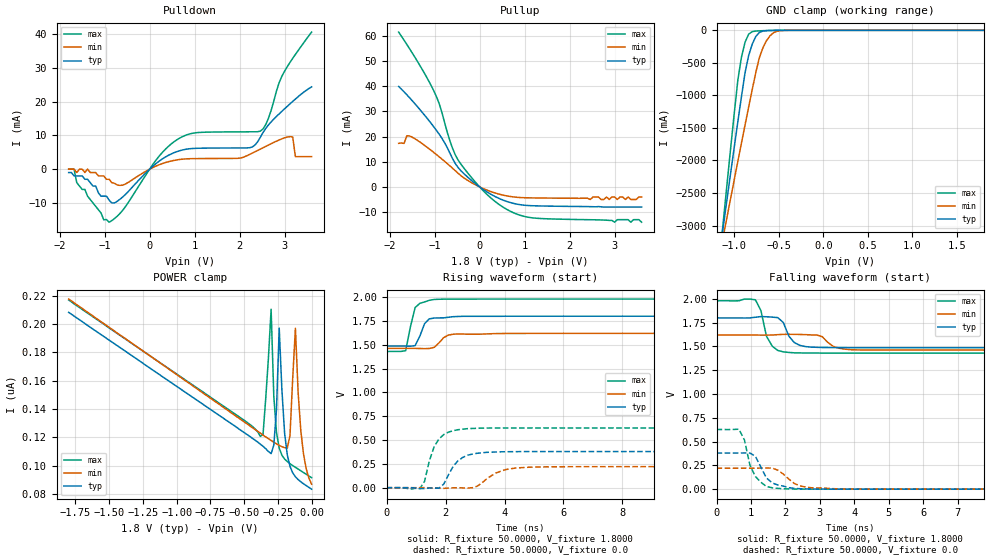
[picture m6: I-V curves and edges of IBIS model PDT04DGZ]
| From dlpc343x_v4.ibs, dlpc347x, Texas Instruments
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[Model]  PDT04DGZ
Model_type 3-state
Polarity   Non-Inverting
Enable   Active-Low
Vmeas =  0.9000V
Cref =   50.0000pF
Rref =   1.0000M
Vref =   0.0V
C_comp   3.2541pF   3.1467pF   3.3974pF
[Temperature Range]   25.0000   0.1250k   -40.0000
[Voltage Range]   1.8000V   1.6200V   1.9800V
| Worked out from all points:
|   slope of the pulldown table from 0 to 0.27 V, typ, clamps not added: 92.6 ohm
|   slope of the pullup table from 0 to 0.27 V, typ, clamps not added: 86.5 ohm
|   GND clamp passes 1 mA (typ) near -0.54 V on its own axis
|   rising waveform, R_fixture 50.0000, V_fixture 1.8000: 20-80 % time 276ps typ, 328ps min, 238ps max; typ from 1.49 V to 1.8 V
|   rising waveform, R_fixture 50.0000, V_fixture 0.0: 20-80 % time 517ps typ, 705ps min, 424ps max; typ from 0 V to 0.379 V
|   falling waveform, R_fixture 50.0000, V_fixture 1.8000: 20-80 % time 282ps typ, 344ps min, 265ps max; typ from 1.8 V to 1.49 V
|   falling waveform, R_fixture 50.0000, V_fixture 0.0: 20-80 % time 398ps typ, 492ps min, 329ps max; typ from 0.379 V to 0 V
[Pulldown]
|Voltage   I(typ)   I(min)   I(max)
-1.8V     -1mA       0A         0A
-1.68V    -2mA       0A         0A
-900mV    -9.2mA     -3mA       -15.7mA
-600mV    -8.247mA   -4.74mA    -12.2mA
180mV     2.06mA     1.128mA    3.334mA
660mV     5.425mA    2.846mA    9.134mA
2.22V     6.337mA    4.345mA    11.06mA
2.52V     10.83mA    6.324mA    11.9mA
2.88V     16.38mA    8.646mA    25.67mA
3.18V     20.05mA    9.514mA    32.79mA
3.24V     20.75mA    3.692mA    33.96mA
3.6V      24.35mA    3.723mA    40.57mA
[Pullup]
|Voltage   I(typ)   I(min)   I(max)
-1.8V     39.86mA    17.29mA    61.43mA
-1.68V    37.72mA    17.27mA    58.22mA
-1.62V    36.59mA    20.27mA    56.57mA
-1.56V    35.43mA    20.24mA    54.9mA
-1.02V    23.85mA    13.67mA    38.14mA
-900mV    20.92mA    11.94mA    33.07mA
-660mV    13.35mA    8.32mA     18.22mA
-480mV    7.708mA    5.429mA    10.67mA
0V        -6.53nA    -5.77nA    -7.26nA
360mV     -3.971mA   -2.5mA     -6.018mA
1.14V     -7.444mA   -4.354mA   -12.2mA
3.6V      -8mA       -4mA       -14mA
[GND_clamp]
|Voltage   I(typ)   I(min)   I(max)
-1.8V     -9.929A    -8.053A    -12.56A
-1.16V    -3.375A    -3.424A    -3.437A
-1.12V    -2.974A    -3.138A    -2.882A
-1.08V    -2.574A    -2.854A    -2.333A
-960mV    -1.399A    -2.009A    -757mA
-920mV    -1.019A    -1.731A    -410.8mA
-880mV    -652.7mA   -1.455A    -184.5mA
-800mV    -215.1mA   -916mA     -20.59mA
-720mV    -33.9mA    -424.5mA   -7.959mA
-680mV    -11.5mA    -271.8mA   -5.67mA
-520mV    -735.3uA   -14.09mA   -620.1uA
1.8V      83.53nA    112.5nA    80.6nA
[POWER_clamp]
|Voltage   I(typ)   I(min)   I(max)
-1.8V     208.3nA    217.7nA    217nA
-380mV    115.3nA    123.1nA    120.8nA
-360mV    113.8nA    121.7nA    122.1nA
-300mV    108.6nA    117.9nA    210.5nA
-280mV    114.6nA    116.7nA    148.9nA
-260mV    139.9nA    115.5nA    123.4nA
-240mV    197.2nA    114.4nA    112.5nA
-200mV    123nA      112.8nA    104.8nA
-160mV    99.55nA    121.6nA    101.5nA
-120mV    92.28nA    197.1nA    98.96nA
-80mV     88.74nA    124.8nA    96.5nA
0V        83.53nA    87.07nA    91.6nA
[Ramp]
| variable   typ   min   max
dV/dt_r  0.2276/0.5113n   0.1324/0.6946n   0.3761/0.4143n
dV/dt_f  0.1878/0.2824n   94.8000m/0.3403n   0.3300/0.2585n
R_load = 50.0000
[Rising Waveform]
R_fixture= 50.0000
V_fixture= 1.8000
V_fixture_min= 1.6200
V_fixture_max= 1.9800
L_fixture= 0.0H
C_fixture= 0.0F
|time   V(typ)   V(min)   V(max)
0s        1.487V     1.462V     1.43V
650ps     1.487V     1.462V     1.438V
810ps     1.485V     1.462V     1.689V
970ps     1.491V     1.462V     1.891V
1.29ns    1.722V     1.46V      1.95V
1.45ns    1.772V     1.461V     1.967V
1.62ns    1.781V     1.474V     1.976V
1.94ns    1.783V     1.576V     1.979V
2.42ns    1.797V     1.614V     1.979V
16ns      1.8V       1.62V      1.98V
[Rising Waveform]
R_fixture= 50.0000
V_fixture= 0.0
V_fixture_min= 0.0
V_fixture_max= 0.0
L_fixture= 0.0H
C_fixture= 0.0F
|time   V(typ)   V(min)   V(max)
0s        1.928uV    2.304uV    1.717uV
1.13ns    -9.545mV   151.8uV    -9.873mV
1.29ns    -8.993mV   264.7uV    67.23mV
1.62ns    -4.421mV   -3.541mV   434.6mV
1.78ns    -4.965mV   -6.062mV   512.2mV
2.42ns    281.6mV    -1.145mV   608.4mV
3.07ns    361.1mV    15.32mV    623.4mV
3.72ns    374.7mV    155.4mV    626.4mV
4.85ns    379.2mV    215.1mV    626.9mV
16ns      379.3mV    220.6mV    626.9mV
[Falling Waveform]
R_fixture= 50.0000
V_fixture= 1.8000
V_fixture_min= 1.6200
V_fixture_max= 1.9800
L_fixture= 0.0H
C_fixture= 0.0F
|time   V(typ)   V(min)   V(max)
0s        1.8V       1.62V      1.98V
1.13ns    1.807V     1.62V      1.99V
1.29ns    1.814V     1.619V     1.876V
1.45ns    1.812V     1.619V     1.607V
1.62ns    1.808V     1.62V      1.502V
1.94ns    1.751V     1.627V     1.443V
2.1ns     1.609V     1.628V     1.437V
2.59ns    1.498V     1.624V     1.431V
4.04ns    1.487V     1.464V     1.43V
16ns      1.487V     1.462V     1.43V
[Falling Waveform]
R_fixture= 50.0000
V_fixture= 0.0
V_fixture_min= 0.0
V_fixture_max= 0.0
L_fixture= 0.0H
C_fixture= 0.0F
|time   V(typ)   V(min)   V(max)
0s        379.3mV    220.6mV    626.9mV
650ps     379.2mV    220.5mV    630.5mV
810ps     380.8mV    220.4mV    517.7mV
970ps     380mV      220.5mV    251.5mV
1.13ns    344.7mV    220.6mV    132.6mV
1.45ns    117mV      222.5mV    28.25mV
1.62ns    65.43mV    220.8mV    14.03mV
2.42ns    4.75mV     35.2mV     669.5uV
3.39ns    268.2uV    5.072mV    4.916uV
16ns      0V         0V         590.4nV
